VERSION 5.8 ;
BUSBITCHARS "[]" ;
DIVIDERCHAR "/" ;
UNITS
    DATABASE MICRONS 1000 ;
END UNITS

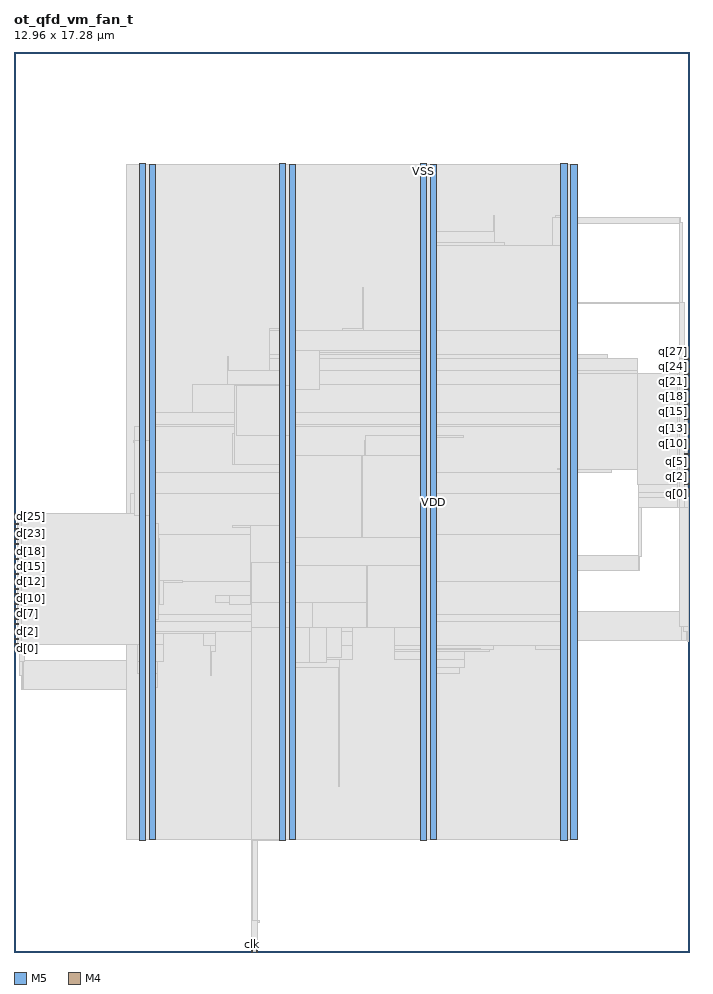
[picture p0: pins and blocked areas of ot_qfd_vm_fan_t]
MACRO ot_qfd_vm_fan_t
  FOREIGN ot_qfd_vm_fan_t 0 0 ;
  CLASS BLOCK ;
  SIZE 12.96 BY 17.28 ;
  PIN clk
    DIRECTION INPUT ;
    USE SIGNAL ;
    PORT
      LAYER M5 ;
        RECT  4.56 0 4.584 0.084 ;
    END
  END clk
  PIN d[0]
    DIRECTION INPUT ;
    USE SIGNAL ;
    PORT
      LAYER M4 ;
        RECT  0 5.808 0.084 5.832 ;
    END
  END d[0]
  PIN d[10]
    DIRECTION INPUT ;
    USE SIGNAL ;
    PORT
      LAYER M4 ;
        RECT  0 6.768 0.084 6.792 ;
    END
  END d[10]
  PIN d[11]
    DIRECTION INPUT ;
    USE SIGNAL ;
    PORT
      LAYER M4 ;
        RECT  0 6.864 0.084 6.888 ;
    END
  END d[11]
  PIN d[12]
    DIRECTION INPUT ;
    USE SIGNAL ;
    PORT
      LAYER M4 ;
        RECT  0 6.96 0.084 6.984 ;
    END
  END d[12]
  PIN d[13]
    DIRECTION INPUT ;
    USE SIGNAL ;
    PORT
      LAYER M4 ;
        RECT  0 7.056 0.084 7.08 ;
    END
  END d[13]
  PIN d[14]
    DIRECTION INPUT ;
    USE SIGNAL ;
    PORT
      LAYER M4 ;
        RECT  0 7.152 0.084 7.176 ;
    END
  END d[14]
  PIN d[15]
    DIRECTION INPUT ;
    USE SIGNAL ;
    PORT
      LAYER M4 ;
        RECT  0 7.248 0.084 7.272 ;
    END
  END d[15]
  PIN d[16]
    DIRECTION INPUT ;
    USE SIGNAL ;
    PORT
      LAYER M4 ;
        RECT  0 7.344 0.084 7.368 ;
    END
  END d[16]
  PIN d[17]
    DIRECTION INPUT ;
    USE SIGNAL ;
    PORT
      LAYER M4 ;
        RECT  0 7.44 0.084 7.464 ;
    END
  END d[17]
  PIN d[18]
    DIRECTION INPUT ;
    USE SIGNAL ;
    PORT
      LAYER M4 ;
        RECT  0 7.536 0.084 7.56 ;
    END
  END d[18]
  PIN d[19]
    DIRECTION INPUT ;
    USE SIGNAL ;
    PORT
      LAYER M4 ;
        RECT  0 7.632 0.084 7.656 ;
    END
  END d[19]
  PIN d[1]
    DIRECTION INPUT ;
    USE SIGNAL ;
    PORT
      LAYER M4 ;
        RECT  0 5.904 0.084 5.928 ;
    END
  END d[1]
  PIN d[20]
    DIRECTION INPUT ;
    USE SIGNAL ;
    PORT
      LAYER M4 ;
        RECT  0 7.728 0.084 7.752 ;
    END
  END d[20]
  PIN d[21]
    DIRECTION INPUT ;
    USE SIGNAL ;
    PORT
      LAYER M4 ;
        RECT  0 7.824 0.084 7.848 ;
    END
  END d[21]
  PIN d[22]
    DIRECTION INPUT ;
    USE SIGNAL ;
    PORT
      LAYER M4 ;
        RECT  0 7.92 0.084 7.944 ;
    END
  END d[22]
  PIN d[23]
    DIRECTION INPUT ;
    USE SIGNAL ;
    PORT
      LAYER M4 ;
        RECT  0 8.016 0.084 8.04 ;
    END
  END d[23]
  PIN d[24]
    DIRECTION INPUT ;
    USE SIGNAL ;
    PORT
      LAYER M4 ;
        RECT  0 8.112 0.084 8.136 ;
    END
  END d[24]
  PIN d[25]
    DIRECTION INPUT ;
    USE SIGNAL ;
    PORT
      LAYER M4 ;
        RECT  0 8.208 0.084 8.232 ;
    END
  END d[25]
  PIN d[26]
    DIRECTION INPUT ;
    USE SIGNAL ;
    PORT
      LAYER M4 ;
        RECT  0 8.304 0.084 8.328 ;
    END
  END d[26]
  PIN d[27]
    DIRECTION INPUT ;
    USE SIGNAL ;
    PORT
      LAYER M4 ;
        RECT  0 8.4 0.084 8.424 ;
    END
  END d[27]
  PIN d[2]
    DIRECTION INPUT ;
    USE SIGNAL ;
    PORT
      LAYER M4 ;
        RECT  0 6 0.084 6.024 ;
    END
  END d[2]
  PIN d[3]
    DIRECTION INPUT ;
    USE SIGNAL ;
    PORT
      LAYER M4 ;
        RECT  0 6.096 0.084 6.12 ;
    END
  END d[3]
  PIN d[4]
    DIRECTION INPUT ;
    USE SIGNAL ;
    PORT
      LAYER M4 ;
        RECT  0 6.192 0.084 6.216 ;
    END
  END d[4]
  PIN d[5]
    DIRECTION INPUT ;
    USE SIGNAL ;
    PORT
      LAYER M4 ;
        RECT  0 6.288 0.084 6.312 ;
    END
  END d[5]
  PIN d[6]
    DIRECTION INPUT ;
    USE SIGNAL ;
    PORT
      LAYER M4 ;
        RECT  0 6.384 0.084 6.408 ;
    END
  END d[6]
  PIN d[7]
    DIRECTION INPUT ;
    USE SIGNAL ;
    PORT
      LAYER M4 ;
        RECT  0 6.48 0.084 6.504 ;
    END
  END d[7]
  PIN d[8]
    DIRECTION INPUT ;
    USE SIGNAL ;
    PORT
      LAYER M4 ;
        RECT  0 6.576 0.084 6.6 ;
    END
  END d[8]
  PIN d[9]
    DIRECTION INPUT ;
    USE SIGNAL ;
    PORT
      LAYER M4 ;
        RECT  0 6.672 0.084 6.696 ;
    END
  END d[9]
  PIN me_e
    DIRECTION INPUT ;
    USE SIGNAL ;
    PORT
      LAYER M5 ;
        RECT  4.656 0 4.68 0.084 ;
    END
  END me_e
  PIN q[0]
    DIRECTION OUTPUT ;
    USE SIGNAL ;
    PORT
      LAYER M4 ;
        RECT  12.876 8.784 12.96 8.808 ;
    END
  END q[0]
  PIN q[10]
    DIRECTION OUTPUT ;
    USE SIGNAL ;
    PORT
      LAYER M4 ;
        RECT  12.876 9.744 12.96 9.768 ;
    END
  END q[10]
  PIN q[11]
    DIRECTION OUTPUT ;
    USE SIGNAL ;
    PORT
      LAYER M4 ;
        RECT  12.876 9.84 12.96 9.864 ;
    END
  END q[11]
  PIN q[12]
    DIRECTION OUTPUT ;
    USE SIGNAL ;
    PORT
      LAYER M4 ;
        RECT  12.876 9.936 12.96 9.96 ;
    END
  END q[12]
  PIN q[13]
    DIRECTION OUTPUT ;
    USE SIGNAL ;
    PORT
      LAYER M4 ;
        RECT  12.876 10.032 12.96 10.056 ;
    END
  END q[13]
  PIN q[14]
    DIRECTION OUTPUT ;
    USE SIGNAL ;
    PORT
      LAYER M4 ;
        RECT  12.876 10.128 12.96 10.152 ;
    END
  END q[14]
  PIN q[15]
    DIRECTION OUTPUT ;
    USE SIGNAL ;
    PORT
      LAYER M4 ;
        RECT  12.876 10.224 12.96 10.248 ;
    END
  END q[15]
  PIN q[16]
    DIRECTION OUTPUT ;
    USE SIGNAL ;
    PORT
      LAYER M4 ;
        RECT  12.876 10.32 12.96 10.344 ;
    END
  END q[16]
  PIN q[17]
    DIRECTION OUTPUT ;
    USE SIGNAL ;
    PORT
      LAYER M4 ;
        RECT  12.876 10.416 12.96 10.44 ;
    END
  END q[17]
  PIN q[18]
    DIRECTION OUTPUT ;
    USE SIGNAL ;
    PORT
      LAYER M4 ;
        RECT  12.876 10.512 12.96 10.536 ;
    END
  END q[18]
  PIN q[19]
    DIRECTION OUTPUT ;
    USE SIGNAL ;
    PORT
      LAYER M4 ;
        RECT  12.876 10.608 12.96 10.632 ;
    END
  END q[19]
  PIN q[1]
    DIRECTION OUTPUT ;
    USE SIGNAL ;
    PORT
      LAYER M4 ;
        RECT  12.876 8.88 12.96 8.904 ;
    END
  END q[1]
  PIN q[20]
    DIRECTION OUTPUT ;
    USE SIGNAL ;
    PORT
      LAYER M4 ;
        RECT  12.876 10.704 12.96 10.728 ;
    END
  END q[20]
  PIN q[21]
    DIRECTION OUTPUT ;
    USE SIGNAL ;
    PORT
      LAYER M4 ;
        RECT  12.876 10.8 12.96 10.824 ;
    END
  END q[21]
  PIN q[22]
    DIRECTION OUTPUT ;
    USE SIGNAL ;
    PORT
      LAYER M4 ;
        RECT  12.876 10.896 12.96 10.92 ;
    END
  END q[22]
  PIN q[23]
    DIRECTION OUTPUT ;
    USE SIGNAL ;
    PORT
      LAYER M4 ;
        RECT  12.876 10.992 12.96 11.016 ;
    END
  END q[23]
  PIN q[24]
    DIRECTION OUTPUT ;
    USE SIGNAL ;
    PORT
      LAYER M4 ;
        RECT  12.876 11.088 12.96 11.112 ;
    END
  END q[24]
  PIN q[25]
    DIRECTION OUTPUT ;
    USE SIGNAL ;
    PORT
      LAYER M4 ;
        RECT  12.876 11.184 12.96 11.208 ;
    END
  END q[25]
  PIN q[26]
    DIRECTION OUTPUT ;
    USE SIGNAL ;
    PORT
      LAYER M4 ;
        RECT  12.876 11.28 12.96 11.304 ;
    END
  END q[26]
  PIN q[27]
    DIRECTION OUTPUT ;
    USE SIGNAL ;
    PORT
      LAYER M4 ;
        RECT  12.876 11.376 12.96 11.4 ;
    END
  END q[27]
  PIN q[2]
    DIRECTION OUTPUT ;
    USE SIGNAL ;
    PORT
      LAYER M4 ;
        RECT  12.876 8.976 12.96 9 ;
    END
  END q[2]
  PIN q[3]
    DIRECTION OUTPUT ;
    USE SIGNAL ;
    PORT
      LAYER M4 ;
        RECT  12.876 9.072 12.96 9.096 ;
    END
  END q[3]
  PIN q[4]
    DIRECTION OUTPUT ;
    USE SIGNAL ;
    PORT
      LAYER M4 ;
        RECT  12.876 9.168 12.96 9.192 ;
    END
  END q[4]
  PIN q[5]
    DIRECTION OUTPUT ;
    USE SIGNAL ;
    PORT
      LAYER M4 ;
        RECT  12.876 9.264 12.96 9.288 ;
    END
  END q[5]
  PIN q[6]
    DIRECTION OUTPUT ;
    USE SIGNAL ;
    PORT
      LAYER M4 ;
        RECT  12.876 9.36 12.96 9.384 ;
    END
  END q[6]
  PIN q[7]
    DIRECTION OUTPUT ;
    USE SIGNAL ;
    PORT
      LAYER M4 ;
        RECT  12.876 9.456 12.96 9.48 ;
    END
  END q[7]
  PIN q[8]
    DIRECTION OUTPUT ;
    USE SIGNAL ;
    PORT
      LAYER M4 ;
        RECT  12.876 9.552 12.96 9.576 ;
    END
  END q[8]
  PIN q[9]
    DIRECTION OUTPUT ;
    USE SIGNAL ;
    PORT
      LAYER M4 ;
        RECT  12.876 9.648 12.96 9.672 ;
    END
  END q[9]
  PIN VDD
    DIRECTION INOUT ;
    USE POWER ;
    PORT
      LAYER M5 ;
        RECT  10.692 2.151 10.812 15.129 ;
        RECT  7.992 2.151 8.112 15.129 ;
        RECT  5.292 2.151 5.412 15.129 ;
        RECT  2.592 2.151 2.712 15.129 ;
    END
  END VDD
  PIN VSS
    DIRECTION INOUT ;
    USE GROUND ;
    PORT
      LAYER M5 ;
        RECT  10.5 2.137 10.62 15.143 ;
        RECT  7.8 2.137 7.92 15.143 ;
        RECT  5.1 2.137 5.22 15.143 ;
        RECT  2.4 2.137 2.52 15.143 ;
    END
  END VSS
  # OT_OBS_CLOSED layer=M5 d_um=1.536 added=7
  OBS
    LAYER RVTN ;
     RECT  2.16 2.16 10.8 2.295 ;
     RECT  2.16 2.565 10.8 2.835 ;
     RECT  2.16 3.105 10.8 3.375 ;
     RECT  2.16 3.645 10.8 3.915 ;
     RECT  2.16 4.185 10.8 4.455 ;
     RECT  2.16 4.725 10.8 4.995 ;
     RECT  2.16 5.265 10.8 5.535 ;
     RECT  2.16 5.805 10.8 6.075 ;
     RECT  2.16 6.345 10.8 6.615 ;
     RECT  2.16 6.885 10.8 7.155 ;
     RECT  2.16 7.425 10.8 7.695 ;
     RECT  2.16 7.965 10.8 8.235 ;
     RECT  2.16 8.505 10.8 8.775 ;
     RECT  2.16 9.045 10.8 9.315 ;
     RECT  2.16 9.585 10.8 9.855 ;
     RECT  2.16 10.125 10.8 10.395 ;
     RECT  2.16 10.665 10.8 10.935 ;
     RECT  2.16 11.205 10.8 11.475 ;
     RECT  2.16 11.745 10.8 12.015 ;
     RECT  2.16 12.285 10.8 12.555 ;
     RECT  2.16 12.825 10.8 13.095 ;
     RECT  2.16 13.365 10.8 13.635 ;
     RECT  2.16 13.905 10.8 14.175 ;
     RECT  2.16 14.445 10.8 14.715 ;
     RECT  2.16 14.985 10.8 15.12 ;
    LAYER RVTP ;
     RECT  2.16 2.295 10.8 2.565 ;
     RECT  2.16 2.835 10.8 3.105 ;
     RECT  2.16 3.375 10.8 3.645 ;
     RECT  2.16 3.915 10.8 4.185 ;
     RECT  2.16 4.455 10.8 4.725 ;
     RECT  2.16 4.995 10.8 5.265 ;
     RECT  2.16 5.535 10.8 5.805 ;
     RECT  2.16 6.075 10.8 6.345 ;
     RECT  2.16 6.615 10.8 6.885 ;
     RECT  2.16 7.155 10.8 7.425 ;
     RECT  2.16 7.695 10.8 7.965 ;
     RECT  2.16 8.235 10.8 8.505 ;
     RECT  2.16 8.775 10.8 9.045 ;
     RECT  2.16 9.315 10.8 9.585 ;
     RECT  2.16 9.855 10.8 10.125 ;
     RECT  2.16 10.395 10.8 10.665 ;
     RECT  2.16 10.935 10.8 11.205 ;
     RECT  2.16 11.475 10.8 11.745 ;
     RECT  2.16 12.015 10.8 12.285 ;
     RECT  2.16 12.555 10.8 12.825 ;
     RECT  2.16 13.095 10.8 13.365 ;
     RECT  2.16 13.635 10.8 13.905 ;
     RECT  2.16 14.175 10.8 14.445 ;
     RECT  2.16 14.715 10.8 14.985 ;
    LAYER M1 ;
     RECT  2.16 2.151 10.8 15.129 ;
    LAYER M2 ;
     RECT  0.103 5.31 0.139 5.328 ;
     RECT  0.139 5.04 0.175 5.328 ;
     RECT  0.175 5.04 2.16 5.598 ;
     RECT  0.535 6.696 2.16 6.714 ;
     RECT  2.16 2.151 10.8 15.129 ;
     RECT  10.8 2.421 10.812 14.859 ;
     RECT  10.812 9.216 11.399 11.466 ;
     RECT  11.399 9.216 11.435 11.394 ;
     RECT  11.435 9.594 11.471 11.394 ;
     RECT  11.471 10.206 11.975 11.394 ;
     RECT  10.812 7.326 12.011 7.614 ;
     RECT  12.011 7.596 12.047 7.614 ;
     RECT  10.812 13.986 12.803 14.094 ;
     RECT  10.812 5.976 12.811 6.534 ;
     RECT  12.803 13.986 12.839 14.004 ;
     RECT  10.812 12.456 12.875 12.474 ;
     RECT  12.811 5.976 12.911 6.876 ;
     RECT  12.911 5.976 12.947 5.994 ;
    LAYER M3 ;
     RECT  4.644 0.571 4.662 2.143 ;
     RECT  4.644 2.143 5.205 2.291 ;
     RECT  2.415 2.143 2.505 2.413 ;
     RECT  5.076 2.291 5.205 2.413 ;
     RECT  7.815 2.143 7.905 2.413 ;
     RECT  10.515 2.143 10.605 2.413 ;
     RECT  5.076 2.413 5.397 3.145 ;
     RECT  5.04 3.145 5.397 3.437 ;
     RECT  2.415 2.413 2.697 5.071 ;
     RECT  0.144 5.035 0.162 5.305 ;
     RECT  2.415 5.071 2.754 5.341 ;
     RECT  7.815 2.413 8.097 5.341 ;
     RECT  5.115 3.437 5.397 5.419 ;
     RECT  4.896 5.419 5.397 5.467 ;
     RECT  6.228 3.181 6.246 5.467 ;
     RECT  7.815 5.341 8.55 5.467 ;
     RECT  0.108 5.305 0.162 5.575 ;
     RECT  2.376 5.341 2.754 5.575 ;
     RECT  4.896 5.467 6.246 5.611 ;
     RECT  7.815 5.467 8.658 5.611 ;
     RECT  3.78 5.305 3.798 5.773 ;
     RECT  7.308 5.611 8.658 5.773 ;
     RECT  7.308 5.773 9.126 5.809 ;
     RECT  10.515 2.413 10.797 5.809 ;
     RECT  0.108 5.575 0.198 5.837 ;
     RECT  3.78 5.773 3.87 5.881 ;
     RECT  4.896 5.611 6.498 5.881 ;
     RECT  7.308 5.809 9.198 5.881 ;
     RECT  10.008 5.809 10.797 5.881 ;
     RECT  2.376 5.575 2.862 5.899 ;
     RECT  2.304 5.899 2.862 6.115 ;
     RECT  3.636 5.881 3.87 6.115 ;
     RECT  2.304 6.115 3.87 6.151 ;
     RECT  4.644 5.881 6.498 6.151 ;
     RECT  12.924 5.971 12.942 6.151 ;
     RECT  0.144 5.837 0.198 6.221 ;
     RECT  12.852 6.151 12.942 6.241 ;
     RECT  2.304 6.151 6.498 6.349 ;
     RECT  7.308 5.881 10.797 6.349 ;
     RECT  2.304 6.349 10.797 6.475 ;
     RECT  0.18 6.221 0.198 6.691 ;
     RECT  0.18 6.691 0.558 6.893 ;
     RECT  2.268 6.475 10.797 7.115 ;
     RECT  11.988 7.321 12.006 7.591 ;
     RECT  0.144 6.955 0.162 7.997 ;
     RECT  2.304 7.115 10.797 8.011 ;
     RECT  11.988 7.591 12.042 8.539 ;
     RECT  12.78 6.241 12.942 8.539 ;
     RECT  11.988 8.539 12.942 8.717 ;
     RECT  2.232 8.011 10.797 8.807 ;
     RECT  11.988 8.717 12.87 8.813 ;
     RECT  11.988 8.813 12.834 9.101 ;
     RECT  11.988 9.101 12.042 9.197 ;
     RECT  2.304 8.807 10.797 9.211 ;
     RECT  12.816 9.101 12.834 9.389 ;
     RECT  2.304 9.211 11.466 10.085 ;
     RECT  2.415 10.085 11.466 10.123 ;
     RECT  2.415 10.123 11.97 10.355 ;
     RECT  3.42 10.355 11.97 10.895 ;
     RECT  4.104 10.895 11.97 11.165 ;
     RECT  12.852 11.179 12.87 11.275 ;
     RECT  12.816 11.275 12.87 11.371 ;
     RECT  4.896 11.165 11.97 11.399 ;
     RECT  4.104 11.165 4.122 11.435 ;
     RECT  4.896 11.399 11.394 11.471 ;
     RECT  4.896 11.471 10.797 11.939 ;
     RECT  4.896 11.939 5.397 11.975 ;
     RECT  6.3 11.939 6.714 11.975 ;
     RECT  12.78 11.371 12.87 12.479 ;
     RECT  6.696 11.975 6.714 12.749 ;
     RECT  7.815 11.939 10.797 13.559 ;
     RECT  7.815 13.559 9.414 13.631 ;
     RECT  7.815 13.631 9.234 13.829 ;
     RECT  12.78 12.479 12.834 14.009 ;
     RECT  10.332 13.559 10.797 14.099 ;
     RECT  12.78 14.009 12.798 14.099 ;
     RECT  9.216 13.829 9.234 14.135 ;
     RECT  10.404 14.099 10.797 14.135 ;
     RECT  2.415 10.355 2.697 14.867 ;
     RECT  5.115 11.975 5.397 14.867 ;
     RECT  7.815 13.829 8.097 14.867 ;
     RECT  10.515 14.135 10.797 14.867 ;
     RECT  2.415 14.867 2.505 15.137 ;
     RECT  5.115 14.867 5.205 15.137 ;
     RECT  7.815 14.867 7.905 15.137 ;
     RECT  10.515 14.867 10.605 15.137 ;
    LAYER M4 ;
     RECT  0.06 5.808 0.137 8.424 ;
     RECT  0.137 5.904 2.408 8.424 ;
     RECT  2.285 9.792 2.408 9.816 ;
     RECT  2.408 2.148 2.512 15.132 ;
     RECT  2.512 2.418 2.704 14.862 ;
     RECT  2.704 6.384 2.765 8.232 ;
     RECT  2.765 6.672 2.801 7.944 ;
     RECT  2.801 6.672 2.873 7.128 ;
     RECT  2.873 7.104 3.233 7.128 ;
     RECT  3.877 6.72 4.129 6.84 ;
     RECT  4.201 9.36 4.237 9.96 ;
     RECT  4.129 6.672 4.549 6.84 ;
     RECT  4.201 8.16 4.549 8.184 ;
     RECT  4.633 0.576 4.717 0.6 ;
     RECT  4.844 5.424 4.885 5.448 ;
     RECT  4.885 3.408 5.108 3.432 ;
     RECT  4.885 5.424 5.108 5.592 ;
     RECT  4.549 6.672 5.108 8.184 ;
     RECT  4.237 9.36 5.108 10.872 ;
     RECT  5.108 2.148 5.212 15.132 ;
     RECT  5.212 2.418 5.404 14.862 ;
     RECT  5.404 5.568 5.681 8.184 ;
     RECT  5.404 10.8 5.861 11.544 ;
     RECT  5.681 5.568 6.005 7.464 ;
     RECT  6.005 5.664 6.293 7.464 ;
     RECT  6.293 6.24 6.661 7.464 ;
     RECT  5.404 9.504 6.721 9.528 ;
     RECT  6.721 9.504 6.757 9.816 ;
     RECT  6.661 6.24 6.797 7.992 ;
     RECT  6.797 6.24 6.803 7.416 ;
     RECT  6.803 6.816 7.808 6.84 ;
     RECT  6.757 9.504 7.808 9.912 ;
     RECT  5.861 11.52 7.808 11.544 ;
     RECT  7.808 2.148 7.912 15.132 ;
     RECT  7.912 2.418 8.104 14.862 ;
     RECT  8.104 9.888 8.633 9.912 ;
     RECT  8.104 5.808 8.957 5.832 ;
     RECT  10.429 9.264 10.508 9.288 ;
     RECT  10.508 2.148 10.612 15.132 ;
     RECT  10.612 2.418 10.804 14.862 ;
     RECT  10.804 9.264 11.977 11.112 ;
     RECT  11.977 8.976 12.733 11.112 ;
     RECT  12.733 8.544 12.769 11.112 ;
     RECT  12.769 8.544 12.881 11.4 ;
     RECT  12.881 8.688 12.924 11.4 ;
     RECT  12.924 8.688 12.953 8.712 ;
    LAYER M5 ;
     RECT  4.56 0.016 4.68 0.611 ;
     RECT  4.56 0.611 4.584 2.137 ;
     RECT  2.4 2.137 2.52 2.151 ;
     RECT  4.56 2.137 5.22 2.151 ;
     RECT  7.8 2.137 7.92 2.151 ;
     RECT  10.5 2.137 10.62 2.151 ;
     RECT  4.56 2.151 5.412 6.229 ;
     RECT  4.56 6.229 5.736 6.707 ;
     RECT  6.768 6.229 6.792 7.427 ;
     RECT  4.56 6.707 5.412 7.475 ;
     RECT  2.4 2.151 2.712 8.389 ;
     RECT  6.672 7.957 6.696 9.539 ;
     RECT  2.304 8.389 2.712 9.827 ;
     RECT  5.1 7.475 5.412 9.925 ;
     RECT  4.272 9.925 5.412 10.883 ;
     RECT  2.4 9.827 2.712 15.129 ;
     RECT  5.1 10.883 5.412 15.129 ;
     RECT  7.8 2.151 8.112 15.129 ;
     RECT  10.5 2.151 10.812 15.129 ;
     RECT  2.4 15.129 2.52 15.143 ;
     RECT  5.1 15.129 5.22 15.143 ;
     RECT  7.8 15.129 7.92 15.143 ;
     RECT  10.5 15.129 10.62 15.143 ;
     RECT  4.584 0.611 4.68 2.137 ;
     RECT  5.736 6.229 6.768 6.707 ;
     RECT  6.792 6.229 7.8 7.427 ;
     RECT  5.412 6.707 6.768 7.427 ;
     RECT  5.412 7.427 7.8 7.957 ;
     RECT  5.412 7.957 6.672 9.539 ;
     RECT  6.696 7.957 7.8 9.539 ;
  END
END ot_qfd_vm_fan_t
END LIBRARY
